VERSION 5.8 ;
BUSBITCHARS "[]" ;
DIVIDERCHAR "/" ;
UNITS
    DATABASE MICRONS 1000 ;
END UNITS

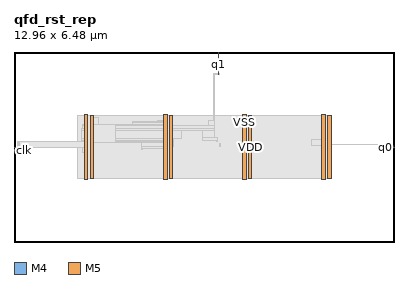
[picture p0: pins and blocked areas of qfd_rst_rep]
MACRO qfd_rst_rep
  FOREIGN qfd_rst_rep 0 0 ;
  CLASS BLOCK ;
  SIZE 12.96 BY 6.48 ;
  PIN clk
    DIRECTION INPUT ;
    USE SIGNAL ;
    PORT
      LAYER M4 ;
        RECT  0 3.12 0.084 3.144 ;
    END
  END clk
  PIN d
    DIRECTION INPUT ;
    USE SIGNAL ;
    PORT
      LAYER M4 ;
        RECT  0 3.216 0.084 3.24 ;
    END
  END d
  PIN q0
    DIRECTION OUTPUT ;
    USE SIGNAL ;
    PORT
      LAYER M4 ;
        RECT  12.876 3.216 12.96 3.24 ;
    END
    PORT
      LAYER M4 ;
        RECT  12.841 3.216 12.924 3.24 ;
    END
  END q0
  PIN q1
    DIRECTION OUTPUT ;
    USE SIGNAL ;
    PORT
      LAYER M5 ;
        RECT  6.96 6.396 6.984 6.48 ;
    END
    PORT
      LAYER M5 ;
        RECT  6.96 5.701 6.984 6.416 ;
    END
  END q1
  PIN VSS
    DIRECTION INOUT ;
    USE GROUND ;
    PORT
      LAYER M5 ;
        RECT  10.5 2.137 10.62 4.343 ;
        RECT  7.8 2.137 7.92 4.343 ;
        RECT  5.1 2.137 5.22 4.343 ;
        RECT  2.4 2.137 2.52 4.343 ;
    END
  END VSS
  PIN VDD
    DIRECTION INOUT ;
    USE POWER ;
    PORT
      LAYER M5 ;
        RECT  10.692 2.151 10.812 4.329 ;
        RECT  7.992 2.151 8.112 4.329 ;
        RECT  5.292 2.151 5.412 4.329 ;
        RECT  2.592 2.151 2.712 4.329 ;
    END
  END VDD
  # OT_OBS_CLOSED layer=M5 d_um=1.536 added=0
  OBS
    LAYER RVTN ;
     RECT  2.16 2.16 10.8 2.295 ;
     RECT  2.16 2.565 10.8 2.835 ;
     RECT  2.16 3.105 10.8 3.375 ;
     RECT  2.16 3.645 10.8 3.915 ;
     RECT  2.16 4.185 10.8 4.32 ;
    LAYER RVTP ;
     RECT  2.16 2.295 10.8 2.565 ;
     RECT  2.16 2.835 10.8 3.105 ;
     RECT  2.16 3.375 10.8 3.645 ;
     RECT  2.16 3.915 10.8 4.185 ;
    LAYER M1 ;
     RECT  2.16 2.151 10.8 4.329 ;
    LAYER M2 ;
     RECT  2.16 2.151 10.8 4.329 ;
     RECT  10.8 2.421 10.812 4.059 ;
     RECT  10.812 3.312 12.875 3.33 ;
    LAYER M3 ;
     RECT  2.415 2.143 2.505 2.413 ;
     RECT  5.115 2.143 5.205 2.413 ;
     RECT  7.815 2.143 7.905 2.413 ;
     RECT  10.515 2.143 10.605 2.413 ;
     RECT  2.415 2.413 2.697 3.037 ;
     RECT  4.356 3.145 4.374 3.181 ;
     RECT  5.115 2.413 5.397 3.181 ;
     RECT  2.34 3.037 2.697 3.211 ;
     RECT  4.356 3.181 5.397 3.271 ;
     RECT  10.515 2.413 10.797 3.307 ;
     RECT  12.852 3.211 12.87 3.335 ;
     RECT  7.02 3.271 7.038 3.371 ;
     RECT  2.304 3.211 2.697 3.403 ;
     RECT  2.304 3.403 3.438 3.451 ;
     RECT  4.356 3.271 5.454 3.451 ;
     RECT  6.912 3.415 6.93 3.451 ;
     RECT  10.152 3.307 10.797 3.479 ;
     RECT  2.304 3.451 5.454 3.541 ;
     RECT  6.444 3.451 6.93 3.569 ;
     RECT  2.304 3.541 5.706 3.811 ;
     RECT  6.444 3.569 6.822 3.811 ;
     RECT  2.304 3.811 6.822 3.875 ;
     RECT  2.34 3.875 6.822 3.983 ;
     RECT  2.34 3.983 5.397 4.013 ;
     RECT  2.34 4.013 2.898 4.019 ;
     RECT  4.032 4.013 5.397 4.067 ;
     RECT  7.815 2.413 8.097 4.067 ;
     RECT  10.515 3.479 10.797 4.067 ;
     RECT  4.032 4.067 5.205 4.109 ;
     RECT  4.896 4.109 5.205 4.145 ;
     RECT  6.624 3.983 6.822 4.145 ;
     RECT  2.415 4.019 2.898 4.253 ;
     RECT  2.415 4.253 2.505 4.337 ;
     RECT  5.115 4.145 5.205 4.337 ;
     RECT  7.815 4.067 7.905 4.337 ;
     RECT  10.515 4.067 10.605 4.337 ;
     RECT  6.804 4.145 6.822 5.741 ;
    LAYER M4 ;
     RECT  0.084 3.12 0.133 3.144 ;
     RECT  0.06 3.144 0.133 3.216 ;
     RECT  0.084 3.216 0.133 3.24 ;
     RECT  0.133 3.12 0.179 3.432 ;
     RECT  0.179 3.216 2.408 3.432 ;
     RECT  2.408 2.148 2.512 4.332 ;
     RECT  2.512 2.418 2.704 4.062 ;
     RECT  2.704 3.408 3.449 4.008 ;
     RECT  3.449 3.408 5.108 3.432 ;
     RECT  5.108 2.148 5.212 4.332 ;
     RECT  5.212 2.418 5.404 4.062 ;
     RECT  6.793 5.712 6.995 5.736 ;
     RECT  7.808 2.148 7.912 4.332 ;
     RECT  7.912 2.418 8.104 4.062 ;
     RECT  10.508 2.148 10.612 4.332 ;
     RECT  10.612 2.418 10.804 4.062 ;
    LAYER M5 ;
     RECT  2.4 2.137 2.52 2.151 ;
     RECT  5.1 2.137 5.22 2.151 ;
     RECT  7.8 2.137 7.92 2.151 ;
     RECT  10.5 2.137 10.62 2.151 ;
     RECT  0.144 3.109 0.168 3.443 ;
     RECT  2.4 2.151 2.712 4.329 ;
     RECT  5.1 2.151 5.412 4.329 ;
     RECT  7.8 2.151 8.112 4.329 ;
     RECT  10.5 2.151 10.812 4.329 ;
     RECT  2.4 4.329 2.52 4.343 ;
     RECT  5.1 4.329 5.22 4.343 ;
     RECT  7.8 4.329 7.92 4.343 ;
     RECT  10.5 4.329 10.62 4.343 ;
  END
END qfd_rst_rep
END LIBRARY
